One B-rep face of a CAD part: STEP entity #115.
In plain terms, the planar face has unit normal (1, 0, 0).
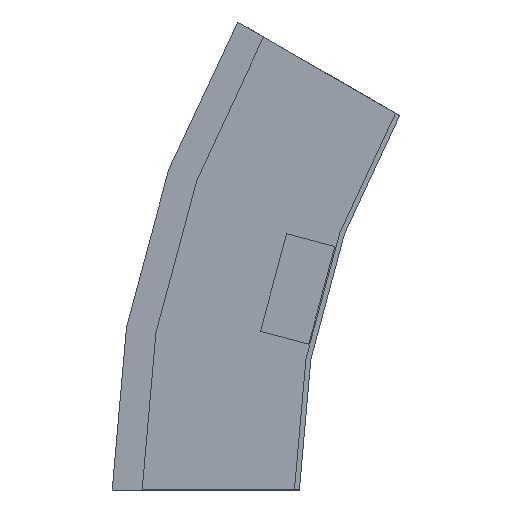
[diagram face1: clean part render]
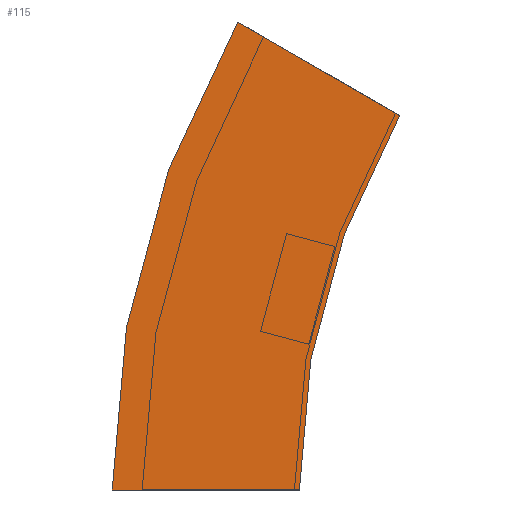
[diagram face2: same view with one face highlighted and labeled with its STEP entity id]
Its self-contained STEP definition (entity closure, numbers rounded to 3 decimals):
#8 = LINE ( 'NONE', #427, #481 ) ;
#41 = PLANE ( 'NONE',  #85 ) ;
#60 = CARTESIAN_POINT ( 'NONE',  ( 0., 0., 0. ) ) ;
#72 = CIRCLE ( 'NONE', #212, 300. ) ;
#80 = CARTESIAN_POINT ( 'NONE',  ( 0., 0., 0. ) ) ;
#85 = AXIS2_PLACEMENT_3D ( 'NONE', #60, #283, #444 ) ;
#115 = ADVANCED_FACE ( 'NONE', ( #279 ), #41, .T. ) ;
#136 = CARTESIAN_POINT ( 'NONE',  ( 0., 75., 0. ) ) ;
#157 = ORIENTED_EDGE ( 'NONE', *, *, #273, .F. ) ;
#161 = ORIENTED_EDGE ( 'NONE', *, *, #294, .T. ) ;
#163 = CARTESIAN_POINT ( 'NONE',  ( 0., 24.76, 187.5 ) ) ;
#165 = VERTEX_POINT ( 'NONE', #163 ) ;
#180 = DIRECTION ( 'NONE',  ( 0., 1., 0. ) ) ;
#191 = CARTESIAN_POINT ( 'NONE',  ( 0., -40.192, 150. ) ) ;
#212 = AXIS2_PLACEMENT_3D ( 'NONE', #229, #442, #180 ) ;
#229 = CARTESIAN_POINT ( 'NONE',  ( 0., -300., 0. ) ) ;
#250 = ORIENTED_EDGE ( 'NONE', *, *, #379, .F. ) ;
#255 = EDGE_CURVE ( 'NONE', #278, #165, #451, .T. ) ;
#273 = EDGE_CURVE ( 'NONE', #482, #331, #72, .T. ) ;
#278 = VERTEX_POINT ( 'NONE', #136 ) ;
#279 = FACE_OUTER_BOUND ( 'NONE', #367, .T. ) ;
#283 = DIRECTION ( 'NONE',  ( 1., 0., 0. ) ) ;
#291 = CARTESIAN_POINT ( 'NONE',  ( 0., -40.192, 150. ) ) ;
#294 = EDGE_CURVE ( 'NONE', #482, #278, #8, .T. ) ;
#328 = DIRECTION ( 'NONE',  ( 0., 0.866, 0.5 ) ) ;
#331 = VERTEX_POINT ( 'NONE', #191 ) ;
#335 = AXIS2_PLACEMENT_3D ( 'NONE', #383, #563, #529 ) ;
#367 = EDGE_LOOP ( 'NONE', ( #547, #250, #157, #161 ) ) ;
#371 = VECTOR ( 'NONE', #328, 1000. ) ;
#379 = EDGE_CURVE ( 'NONE', #331, #165, #494, .T. ) ;
#383 = CARTESIAN_POINT ( 'NONE',  ( 0., -300., 0. ) ) ;
#427 = CARTESIAN_POINT ( 'NONE',  ( 0., 0., 0. ) ) ;
#442 = DIRECTION ( 'NONE',  ( 1., 0., 0. ) ) ;
#444 = DIRECTION ( 'NONE',  ( 0., 0., -1. ) ) ;
#451 = CIRCLE ( 'NONE', #335, 375. ) ;
#481 = VECTOR ( 'NONE', #533, 1000. ) ;
#482 = VERTEX_POINT ( 'NONE', #80 ) ;
#494 = LINE ( 'NONE', #291, #371 ) ;
#529 = DIRECTION ( 'NONE',  ( 0., 1., 0. ) ) ;
#533 = DIRECTION ( 'NONE',  ( 0., 1., 0. ) ) ;
#547 = ORIENTED_EDGE ( 'NONE', *, *, #255, .T. ) ;
#563 = DIRECTION ( 'NONE',  ( 1., 0., 0. ) ) ;
